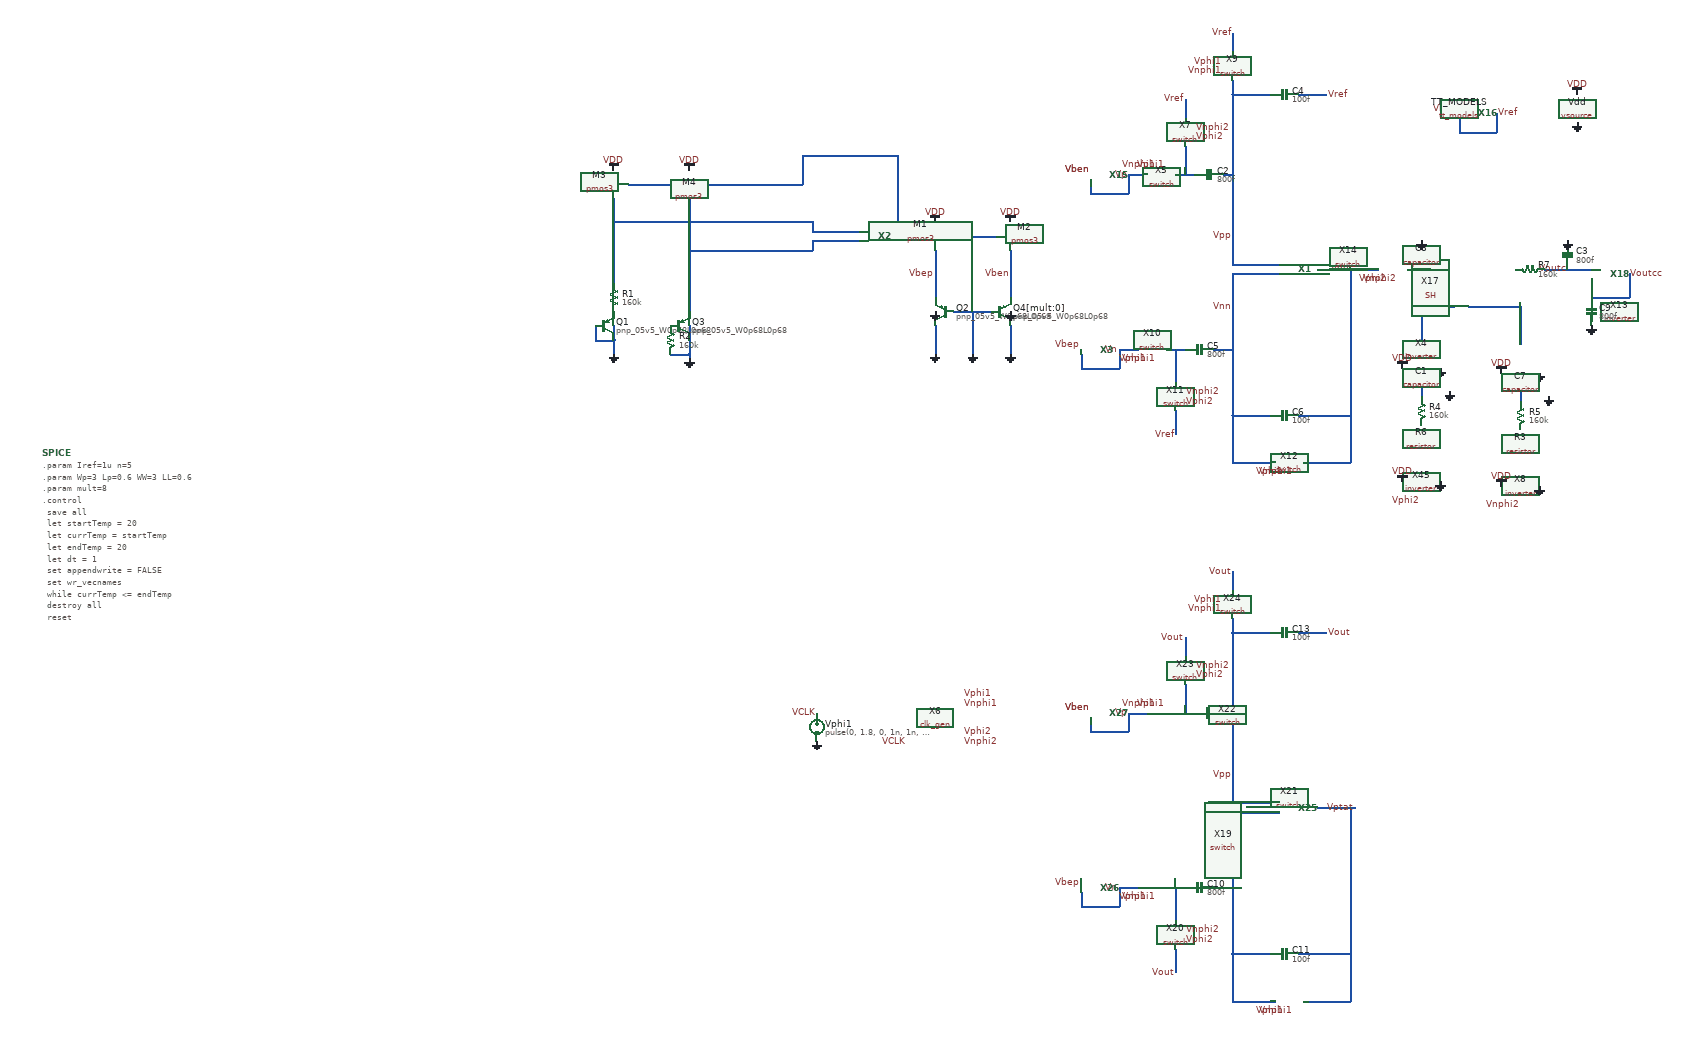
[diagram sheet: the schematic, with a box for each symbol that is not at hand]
v {xschem version=2.9.9 file_version=1.2 }
G {}
K {}
V {}
S {}
E {}
N 610 -70 670 -70 { lab=Vout}
N 410 10 410 40 { lab=Vnn}
N -60 -40 -60 -10 { lab=Vben}
N -60 -110 -60 -40 { lab=Vben}
N -220 -110 -220 -10 { lab=Vbep}
N -300 -140 -250 -140 { lab=#net1}
N -250 -140 -90 -140 { lab=#net1}
N -900 50 -900 80 { lab=GND}
N -940 50 -940 80 { lab=GND}
N -940 80 -900 80 { lab=GND}
N -900 80 -900 110 { lab=GND}
N -740 50 -740 80 { lab=GND}
N -740 80 -740 110 { lab=GND}
N -780 110 -740 110 { lab=GND}
N -740 110 -740 120 { lab=GND}
N -740 -110 -740 20 { lab=#net2}
N -740 -110 -480 -110 { lab=#net2}
N -900 -170 -480 -170 { lab=#net3}
N -900 -170 -900 -40 { lab=#net3}
N -500 -310 -500 -250 { lab=#net1}
N -500 -310 -300 -310 { lab=#net1}
N -300 -310 -300 -140 { lab=#net1}
N -870 -250 -710 -250 { lab=#net1}
N -710 -250 -500 -250 { lab=#net1}
N -740 -220 -740 -110 { lab=#net2}
N -900 -220 -900 -170 { lab=#net3}
N -180 20 -100 20 { lab=GND}
N -60 50 -60 110 { lab=GND}
N -220 50 -220 110 { lab=GND}
N -140 20 -140 80 { lab=GND}
N -140 80 -140 110 { lab=GND}
N 410 100 410 240 { lab=Vnn}
N 410 240 490 240 { lab=Vnn}
N 410 340 500 340 { lab=Vnn}
N 410 240 410 340 { lab=Vnn}
N 660 70 660 240 { lab=Vout}
N 550 240 660 240 { lab=Vout}
N 560 340 660 340 { lab=Vout}
N 660 240 660 340 { lab=Vout}
N 290 100 290 170 { lab=#net4}
N 270 100 310 100 { lab=#net4}
N 170 100 210 100 { lab=Vn}
N 290 230 290 280 { lab=Vref}
N 370 100 410 100 { lab=Vnn}
N 410 40 410 100 { lab=Vnn}
N 660 -70 660 70 { lab=Vout}
N 410 -440 410 -270 { lab=Vpp}
N 410 -440 490 -440 { lab=Vpp}
N 410 -470 410 -440 { lab=Vpp}
N 310 -330 310 -270 { lab=#net5}
N 290 -270 330 -270 { lab=#net5}
N 190 -270 230 -270 { lab=Vp}
N 550 -440 610 -440 { lab=Vref}
N 410 -570 410 -530 { lab=Vref}
N 310 -430 310 -390 { lab=Vref}
N 410 -40 410 10 { lab=Vnn}
N 410 -270 410 -100 { lab=Vpp}
N 390 -270 410 -270 { lab=Vpp}
N 410 -60 410 -40 { lab=Vnn}
N 410 -100 410 -80 { lab=Vpp}
N 590 -70 610 -70 { lab=Vout}
N -480 -150 -380 -150 { lab=#net3}
N -480 -170 -480 -150 { lab=#net3}
N -480 -130 -480 -110 { lab=#net2}
N -480 -130 -380 -130 { lab=#net2}
N 410 -60 510 -60 { lab=Vnn}
N 410 -80 510 -80 { lab=Vpp}
N 90 110 90 140 { lab=Vn}
N 90 140 170 140 { lab=Vn}
N 170 100 170 140 { lab=Vn}
N 110 -260 110 -230 { lab=Vp}
N 110 -230 190 -230 { lab=Vp}
N 190 -270 190 -230 { lab=Vp}
N 890 -390 890 -360 { lab=Vref}
N 890 -360 970 -360 { lab=Vref}
N 970 -400 970 -360 { lab=Vref}
N 1070 -70 1120 -70 { lab=Voutc}
N 810 180 810 200 { lab=#net6}
N 1020 190 1020 210 { lab=#net7}
N 810 10 810 80 { lab=#net8}
N 810 10 880 10 { lab=#net8}
N 910 10 1020 10 { lab=#net9}
N 1020 10 1020 90 { lab=#net9}
N 780 -70 830 -70 { lab=#net10}
N 670 -70 720 -70 { lab=Vout}
N 1120 -70 1170 -70 { lab=Voutc}
N 1170 -50 1170 -10 { lab=Voutcc}
N 1170 -10 1250 -10 { lab=Voutcc}
N 1250 -60 1250 -10 { lab=Voutcc}
N 610 1070 670 1070 { lab=Vptat}
N 410 1150 410 1180 { lab=Vnn}
N 410 1240 410 1380 { lab=Vnn}
N 410 1380 490 1380 { lab=Vnn}
N 410 1480 500 1480 { lab=Vnn}
N 410 1380 410 1480 { lab=Vnn}
N 660 1210 660 1380 { lab=Vptat}
N 550 1380 660 1380 { lab=Vptat}
N 560 1480 660 1480 { lab=Vptat}
N 660 1380 660 1480 { lab=Vptat}
N 290 1240 290 1310 { lab=#net11}
N 270 1240 310 1240 { lab=#net11}
N 170 1240 210 1240 { lab=Vn}
N 290 1370 290 1420 { lab=Vout}
N 370 1240 410 1240 { lab=Vnn}
N 410 1180 410 1240 { lab=Vnn}
N 660 1070 660 1210 { lab=Vptat}
N 410 700 410 870 { lab=Vpp}
N 410 700 490 700 { lab=Vpp}
N 410 670 410 700 { lab=Vpp}
N 310 810 310 870 { lab=#net12}
N 290 870 330 870 { lab=#net12}
N 190 870 230 870 { lab=Vp}
N 550 700 610 700 { lab=Vout}
N 410 570 410 610 { lab=#net13}
N 310 710 310 750 { lab=#net14}
N 410 1100 410 1150 { lab=Vnn}
N 410 870 410 1040 { lab=Vpp}
N 390 870 410 870 { lab=Vpp}
N 410 1080 410 1100 { lab=Vnn}
N 410 1040 410 1060 { lab=Vpp}
N 590 1070 610 1070 { lab=Vptat}
N 410 1080 510 1080 { lab=Vnn}
N 410 1060 510 1060 { lab=Vpp}
N 90 1250 90 1280 { lab=Vn}
N 90 1280 170 1280 { lab=Vn}
N 170 1240 170 1280 { lab=Vn}
N 110 880 110 910 { lab=Vp}
N 110 910 190 910 { lab=Vp}
N 190 870 190 910 { lab=Vp}
C {madvlsi/vsource.sym} 1140 -410 0 0 {name=Vdd
value=1.8}
C {madvlsi/vdd.sym} 1140 -440 0 0 {name=l3 lab=VDD}
C {madvlsi/gnd.sym} 1140 -380 0 0 {name=l4 lab=GND}
C {devices/lab_pin.sym} 670 -70 1 0 {name=l12 sig_type=std_logic lab=Vout}
C {devices/code_shown.sym} -2110 320 0 0 {name=SPICE only_toplevel=false value=".param Iref=1u n=5 
.param Wp=3 Lp=0.6 WW=3 LL=0.6
.param mult=8
.control
  save all
  let startTemp = 20
  let currTemp = startTemp
  let endTemp = 20
  let dt = 1
  set appendwrite = FALSE
  set wr_vecnames
  while currTemp <= endTemp
    destroy all
    reset
    option temp=$&currTemp
    tran 1.2u 120u
*wrdata /home/madvlsi/Documents/MADVLSI-Final_Project/schematic/data/SCbandgap\{$&currTemp\}C7p75refVben12u.csv v(vbep) v(vben) v(vout) v(vphi1) v(vphi2) v(vref) v(voutc) v(voutcc) currTemp
    let currTemp = currTemp + dt
  end
plot v(Vout) v(Voutc) v(Voutcc)
plot v(Voutc)
*8.0*(v(Vbep)-v(Vben))+v(Vben)
.endc
.OPTIONS ITL1=300  ITL2=100"}
C {sky130_fd_pr/pnp_05v5.sym} -200 20 0 1 {name=Q2
model=pnp_05v5_W0p68L0p68
spiceprefix=X
}
C {madvlsi/vdd.sym} -220 -170 0 0 {name=l2 lab=VDD}
C {madvlsi/vdd.sym} -60 -170 0 0 {name=l5 lab=VDD}
C {devices/lab_pin.sym} -220 -60 0 0 {name=l10 sig_type=std_logic lab=Vbep}
C {devices/lab_pin.sym} -60 -60 0 0 {name=l11 sig_type=std_logic lab=Vben}
C {madvlsi/pmos3.sym} -220 -140 0 0 {name=M1
L=Lp
W=Wp
body=VDD
nf=1
mult=mult
ad="'int((nf+1)/2) * W/nf * 0.29'" 
pd="'2*int((nf+1)/2) * (W/nf + 0.29)'"
as="'int((nf+2)/2) * W/nf * 0.29'" 
ps="'2*int((nf+2)/2) * (W/nf + 0.29)'"
nrd="'0.29 / W'" nrs="'0.29 / W'"
sa=0 sb=0 sd=0
model=pfet_01v8
spiceprefix=X
}
C {madvlsi/pmos3.sym} -60 -140 0 0 {name=M2
L=Lp
W=Wp
body=VDD
nf=1
mult=1
ad="'int((nf+1)/2) * W/nf * 0.29'" 
pd="'2*int((nf+1)/2) * (W/nf + 0.29)'"
as="'int((nf+2)/2) * W/nf * 0.29'" 
ps="'2*int((nf+2)/2) * (W/nf + 0.29)'"
nrd="'0.29 / W'" nrs="'0.29 / W'"
sa=0 sb=0 sd=0
model=pfet_01v8
spiceprefix=X
}
C {sky130_fd_pr/pnp_05v5.sym} -80 20 0 0 {name=Q4[mult:0]
model=pnp_05v5_W0p68L0p68
spiceprefix=X
}
C {sky130_fd_pr/pnp_05v5.sym} -920 50 0 0 {name=Q1
model=pnp_05v5_W0p68L0p68
spiceprefix=X
}
C {madvlsi/gnd.sym} -900 110 0 0 {name=l19 lab=GND}
C {sky130_fd_pr/pnp_05v5.sym} -760 50 0 0 {name=Q3
model=pnp_05v5_W0p68L0p68
spiceprefix=X
}
C {madvlsi/gnd.sym} -740 120 0 0 {name=l20 lab=GND}
C {madvlsi/resistor.sym} -900 -10 0 0 {name=R1
value=160k
m=1}
C {madvlsi/resistor.sym} -780 80 0 0 {name=R2
value=160k
m=mult}
C {madvlsi/pmos3.sym} -900 -250 0 1 {name=M3
L=Lp
W=Wp
body=VDD
nf=1
mult=1
ad="'int((nf+1)/2) * W/nf * 0.29'" 
pd="'2*int((nf+1)/2) * (W/nf + 0.29)'"
as="'int((nf+2)/2) * W/nf * 0.29'" 
ps="'2*int((nf+2)/2) * (W/nf + 0.29)'"
nrd="'0.29 / W'" nrs="'0.29 / W'"
sa=0 sb=0 sd=0
model=pfet_01v8
spiceprefix=X
}
C {madvlsi/pmos3.sym} -740 -250 0 1 {name=M4
L=Lp
W=Wp
body=VDD
nf=1
mult=mult
ad="'int((nf+1)/2) * W/nf * 0.29'" 
pd="'2*int((nf+1)/2) * (W/nf + 0.29)'"
as="'int((nf+2)/2) * W/nf * 0.29'" 
ps="'2*int((nf+2)/2) * (W/nf + 0.29)'"
nrd="'0.29 / W'" nrs="'0.29 / W'"
sa=0 sb=0 sd=0
model=pfet_01v8
spiceprefix=X
}
C {madvlsi/vdd.sym} -740 -280 0 0 {name=l21 lab=VDD}
C {madvlsi/vdd.sym} -900 -280 0 0 {name=l22 lab=VDD}
C {madvlsi/gnd.sym} -220 20 1 1 {name=l25 lab=GND}
C {madvlsi/gnd.sym} -60 20 3 1 {name=l26 lab=GND}
C {madvlsi/gnd.sym} -60 110 0 1 {name=l27 lab=GND}
C {madvlsi/gnd.sym} -220 110 0 1 {name=l28 lab=GND}
C {madvlsi/gnd.sym} -140 110 0 1 {name=l29 lab=GND}
C {devices/lab_pin.sym} 410 -140 0 0 {name=l6 sig_type=std_logic lab=Vpp}
C {devices/lab_pin.sym} 410 10 0 0 {name=l13 sig_type=std_logic lab=Vnn}
C {madvlsi/capacitor.sym} 340 100 1 0 {name=C5
value=800f
m=1}
C {madvlsi/capacitor.sym} 520 240 1 0 {name=C6
value=100f
m=1}
C {/home/madvlsi/Documents/MADVLSI-Final_Project/schematic/switch.sym} 240 100 0 0 {name=X10}
C {/home/madvlsi/Documents/MADVLSI-Final_Project/schematic/switch.sym} 290 200 3 0 {name=X11}
C {/home/madvlsi/Documents/MADVLSI-Final_Project/schematic/switch.sym} 530 340 0 0 {name=X12}
C {devices/lab_pin.sym} 290 280 3 0 {name=l1 sig_type=std_logic lab=Vref}
C {devices/lab_pin.sym} 520 360 3 0 {name=l31 sig_type=std_logic lab=Vphi1}
C {devices/lab_pin.sym} 540 360 3 0 {name=l32 sig_type=std_logic lab=Vnphi1}
C {devices/lab_pin.sym} 230 120 3 0 {name=l33 sig_type=std_logic lab=Vphi1}
C {devices/lab_pin.sym} 250 120 3 0 {name=l50 sig_type=std_logic lab=Vnphi1}
C {devices/lab_pin.sym} 310 210 2 0 {name=l51 sig_type=std_logic lab=Vphi2}
C {madvlsi/capacitor.sym} 360 -270 1 0 {name=C2
value=800f
m=1}
C {madvlsi/capacitor.sym} 520 -440 1 0 {name=C4
value=100f
m=1}
C {/home/madvlsi/Documents/MADVLSI-Final_Project/schematic/switch.sym} 260 -270 2 0 {name=X5}
C {/home/madvlsi/Documents/MADVLSI-Final_Project/schematic/switch.sym} 310 -360 3 0 {name=X7}
C {/home/madvlsi/Documents/MADVLSI-Final_Project/schematic/switch.sym} 410 -500 1 0 {name=X9}
C {devices/lab_pin.sym} 410 -570 1 0 {name=l36 sig_type=std_logic lab=Vref}
C {devices/lab_pin.sym} 310 -430 1 0 {name=l38 sig_type=std_logic lab=Vref}
C {devices/lab_pin.sym} 270 -290 1 0 {name=l44 sig_type=std_logic lab=Vphi1}
C {devices/lab_pin.sym} 250 -290 1 0 {name=l49 sig_type=std_logic lab=Vnphi1}
C {devices/lab_pin.sym} 330 -350 2 0 {name=l52 sig_type=std_logic lab=Vphi2}
C {devices/lab_pin.sym} 330 -370 2 0 {name=l53 sig_type=std_logic lab=Vnphi2}
C {devices/lab_pin.sym} 610 -440 2 0 {name=l54 sig_type=std_logic lab=Vref}
C {devices/lab_pin.sym} 970 -400 2 0 {name=l56 sig_type=std_logic lab=Vref}
C {madvlsi/vsource.sym} -470 900 0 0 {name=Vphi1
value="pulse(0, 1.8, 0, 1n, 1n, 6u, 12u)"}
C {madvlsi/gnd.sym} -470 930 0 0 {name=l30 lab=GND}
C {devices/lab_pin.sym} -160 830 2 0 {name=l58 sig_type=std_logic lab=Vphi1}
C {devices/lab_pin.sym} -160 850 2 0 {name=l62 sig_type=std_logic lab=Vnphi1}
C {devices/lab_pin.sym} -160 930 2 0 {name=l68 sig_type=std_logic lab=Vnphi2}
C {devices/lab_pin.sym} 310 190 2 0 {name=l34 sig_type=std_logic lab=Vnphi2}
C {devices/lab_pin.sym} 190 -270 1 0 {name=l35 sig_type=std_logic lab=Vp}
C {devices/lab_pin.sym} 170 100 1 0 {name=l37 sig_type=std_logic lab=Vn}
C {devices/lab_pin.sym} 390 -510 0 0 {name=l39 sig_type=std_logic lab=Vphi1}
C {devices/lab_pin.sym} 390 -490 0 0 {name=l40 sig_type=std_logic lab=Vnphi1}
C {/home/madvlsi/Documents/MADVLSI-Final_Project/schematic/selfbiasedcascode2stage.sym} -340 -140 0 0 {name=X2}
C {/home/madvlsi/Documents/MADVLSI-Final_Project/schematic/selfbiasedcascode2stage.sym} 550 -70 0 0 {name=X1}
C {/home/madvlsi/Documents/MADVLSI-Final_Project/schematic/selfbiasedcascode2stage.sym} 130 100 0 0 {name=X3}
C {devices/lab_pin.sym} 90 90 0 0 {name=l8 sig_type=std_logic lab=Vbep}
C {devices/lab_pin.sym} 110 -280 0 0 {name=l9 sig_type=std_logic lab=Vben}
C {/home/madvlsi/Documents/MADVLSI-Final_Project/schematic/selfbiasedcascode2stage.sym} 150 -270 0 0 {name=X15}
C {devices/lab_pin.sym} 110 -280 0 0 {name=l14 sig_type=std_logic lab=Vben}
C {/home/madvlsi/Documents/MADVLSI-Final_Project/schematic/selfbiasedcascode2stage.sym} 930 -400 0 0 {name=X16}
C {devices/lab_pin.sym} 890 -410 0 0 {name=l15 sig_type=std_logic lab=Vben}
C {madvlsi/tt_models.sym} 650 -360 0 0 {
name=TT_MODELS
only_toplevel=false
value=".option wnflag=1
.param MC_SWITCH=0.0
.lib /media/qdeng/526448C32060CF5C/skywater/skywater-pdk/libraries/sky130_fd_pr_ngspice/latest/models/sky130.lib.spice tt"
}
C {/home/madvlsi/Documents/MADVLSI-Final_Project/schematic/SH.sym} 800 -70 0 0 {name=X17}
C {devices/lab_pin.sym} 1120 -70 3 0 {name=l18 sig_type=std_logic lab=Voutc}
C {madvlsi/capacitor.sym} 1120 -100 0 0 {name=C3
value=800f
m=1}
C {madvlsi/gnd.sym} 1120 -130 2 0 {name=l47 lab=GND}
C {devices/lab_pin.sym} 810 420 3 0 {name=l23 sig_type=std_logic lab=Vphi2}
C {devices/lab_pin.sym} 1020 430 3 0 {name=l24 sig_type=std_logic lab=Vnphi2}
C {/home/madvlsi/Documents/MADVLSI-Final_Project/schematic/clk_gen.sym} -220 880 0 0 {name=X6 Wp=1 Lp=0.15 WW=1 LL=0.15}
C {devices/lab_pin.sym} -160 910 2 0 {name=l7 sig_type=std_logic lab=Vphi2}
C {devices/lab_pin.sym} -470 870 1 0 {name=l16 sig_type=std_logic lab=VCLK}
C {devices/lab_pin.sym} -280 930 0 0 {name=l17 sig_type=std_logic lab=VCLK}
C {/home/madvlsi/Documents/MADVLSI-Final_Project/schematic/inverter.sym} 810 380 3 0 {name=X45 Wp=1 Lp=0.15 WW=1 LL=0.15}
C {madvlsi/vdd.sym} 770 380 3 0 {name=l87 lab=VDD}
C {madvlsi/gnd.sym} 850 380 3 0 {name=l88 lab=GND}
C {/home/madvlsi/Documents/MADVLSI-Final_Project/schematic/inverter.sym} 810 140 3 0 {name=X4 Wp=1 Lp=0.15 WW=1 LL=0.15}
C {madvlsi/vdd.sym} 770 140 3 0 {name=l41 lab=VDD}
C {madvlsi/gnd.sym} 850 140 3 0 {name=l42 lab=GND}
C {madvlsi/capacitor.sym} 840 190 1 0 {name=C1
value=800f
m=1}
C {madvlsi/gnd.sym} 870 190 3 0 {name=l43 lab=GND}
C {/home/madvlsi/Documents/MADVLSI-Final_Project/schematic/inverter.sym} 1020 390 3 0 {name=X8 Wp=1 Lp=0.15 WW=1 LL=0.15}
C {madvlsi/vdd.sym} 980 390 3 0 {name=l45 lab=VDD}
C {madvlsi/gnd.sym} 1060 390 3 0 {name=l46 lab=GND}
C {/home/madvlsi/Documents/MADVLSI-Final_Project/schematic/inverter.sym} 1020 150 3 0 {name=X13 Wp=1 Lp=0.15 WW=1 LL=0.15}
C {madvlsi/vdd.sym} 980 150 3 0 {name=l48 lab=VDD}
C {madvlsi/gnd.sym} 1060 150 3 0 {name=l55 lab=GND}
C {madvlsi/capacitor.sym} 1050 200 1 0 {name=C7
value=800f
m=1}
C {madvlsi/gnd.sym} 1080 200 3 0 {name=l57 lab=GND}
C {madvlsi/resistor.sym} 810 230 0 0 {name=R4
value=160k
m=1}
C {madvlsi/resistor.sym} 1020 240 0 0 {name=R5
value=160k
m=1}
C {/home/madvlsi/Documents/MADVLSI-Final_Project/schematic/switch.sym} 750 -70 0 0 {name=X14}
C {devices/lab_pin.sym} 740 -50 3 0 {name=l59 sig_type=std_logic lab=Vphi2}
C {devices/lab_pin.sym} 760 -50 3 0 {name=l60 sig_type=std_logic lab=Vnphi2}
C {madvlsi/capacitor.sym} 810 -100 0 0 {name=C8
value=800f
m=1}
C {madvlsi/gnd.sym} 810 -130 2 0 {name=l61 lab=GND}
C {madvlsi/resistor.sym} 1020 300 0 0 {name=R3
value=160k
m=1}
C {madvlsi/resistor.sym} 810 290 0 0 {name=R6
value=160k
m=1}
C {madvlsi/resistor.sym} 1040 -70 1 0 {name=R7
value=160k
m=1}
C {/home/madvlsi/Documents/MADVLSI-Final_Project/schematic/selfbiasedcascode2stage.sym} 1210 -60 0 0 {name=X18}
C {devices/lab_pin.sym} 1250 -60 2 0 {name=l63 sig_type=std_logic lab=Voutcc}
C {madvlsi/capacitor.sym} 1170 20 0 0 {name=C9
value=800f
m=1}
C {madvlsi/gnd.sym} 1170 50 0 0 {name=l64 lab=GND}
C {devices/lab_pin.sym} 670 1070 1 0 {name=l65 sig_type=std_logic lab=Vptat}
C {devices/lab_pin.sym} 410 1000 0 0 {name=l66 sig_type=std_logic lab=Vpp}
C {devices/lab_pin.sym} 410 1150 0 0 {name=l67 sig_type=std_logic lab=Vnn}
C {madvlsi/capacitor.sym} 340 1240 1 0 {name=C10
value=800f
m=1}
C {madvlsi/capacitor.sym} 520 1380 1 0 {name=C11
value=100f
m=1}
C {/home/madvlsi/Documents/MADVLSI-Final_Project/schematic/switch.sym} 240 1240 0 0 {name=X19}
C {/home/madvlsi/Documents/MADVLSI-Final_Project/schematic/switch.sym} 290 1340 3 0 {name=X20}
C {/home/madvlsi/Documents/MADVLSI-Final_Project/schematic/switch.sym} 530 1480 0 0 {name=X21}
C {devices/lab_pin.sym} 520 1500 3 0 {name=l70 sig_type=std_logic lab=Vphi1}
C {devices/lab_pin.sym} 540 1500 3 0 {name=l71 sig_type=std_logic lab=Vnphi1}
C {devices/lab_pin.sym} 230 1260 3 0 {name=l72 sig_type=std_logic lab=Vphi1}
C {devices/lab_pin.sym} 250 1260 3 0 {name=l73 sig_type=std_logic lab=Vnphi1}
C {devices/lab_pin.sym} 310 1350 2 0 {name=l74 sig_type=std_logic lab=Vphi2}
C {madvlsi/capacitor.sym} 360 870 1 0 {name=C12
value=800f
m=1}
C {madvlsi/capacitor.sym} 520 700 1 0 {name=C13
value=100f
m=1}
C {/home/madvlsi/Documents/MADVLSI-Final_Project/schematic/switch.sym} 260 870 2 0 {name=X22}
C {/home/madvlsi/Documents/MADVLSI-Final_Project/schematic/switch.sym} 310 780 3 0 {name=X23}
C {/home/madvlsi/Documents/MADVLSI-Final_Project/schematic/switch.sym} 410 640 1 0 {name=X24}
C {devices/lab_pin.sym} 270 850 1 0 {name=l77 sig_type=std_logic lab=Vphi1}
C {devices/lab_pin.sym} 250 850 1 0 {name=l78 sig_type=std_logic lab=Vnphi1}
C {devices/lab_pin.sym} 330 790 2 0 {name=l79 sig_type=std_logic lab=Vphi2}
C {devices/lab_pin.sym} 330 770 2 0 {name=l80 sig_type=std_logic lab=Vnphi2}
C {devices/lab_pin.sym} 310 1330 2 0 {name=l82 sig_type=std_logic lab=Vnphi2}
C {devices/lab_pin.sym} 190 870 1 0 {name=l83 sig_type=std_logic lab=Vp}
C {devices/lab_pin.sym} 170 1240 1 0 {name=l84 sig_type=std_logic lab=Vn}
C {devices/lab_pin.sym} 390 630 0 0 {name=l85 sig_type=std_logic lab=Vphi1}
C {devices/lab_pin.sym} 390 650 0 0 {name=l86 sig_type=std_logic lab=Vnphi1}
C {/home/madvlsi/Documents/MADVLSI-Final_Project/schematic/selfbiasedcascode2stage.sym} 550 1070 0 0 {name=X25}
C {/home/madvlsi/Documents/MADVLSI-Final_Project/schematic/selfbiasedcascode2stage.sym} 130 1240 0 0 {name=X26}
C {devices/lab_pin.sym} 90 1230 0 0 {name=l89 sig_type=std_logic lab=Vbep}
C {devices/lab_pin.sym} 110 860 0 0 {name=l90 sig_type=std_logic lab=Vben}
C {/home/madvlsi/Documents/MADVLSI-Final_Project/schematic/selfbiasedcascode2stage.sym} 150 870 0 0 {name=X27}
C {devices/lab_pin.sym} 110 860 0 0 {name=l91 sig_type=std_logic lab=Vben}
C {devices/lab_pin.sym} 610 700 2 0 {name=l81 sig_type=std_logic lab=Vout}
C {devices/lab_pin.sym} 290 1420 3 0 {name=l92 sig_type=std_logic lab=Vout}
C {devices/lab_pin.sym} 410 570 1 0 {name=l69 sig_type=std_logic lab=Vout}
C {devices/lab_pin.sym} 310 710 1 0 {name=l75 sig_type=std_logic lab=Vout}
